VERSION 5.8 ;
BUSBITCHARS "[]" ;
DIVIDERCHAR "/" ;
UNITS
    DATABASE MICRONS 1000 ;
END UNITS

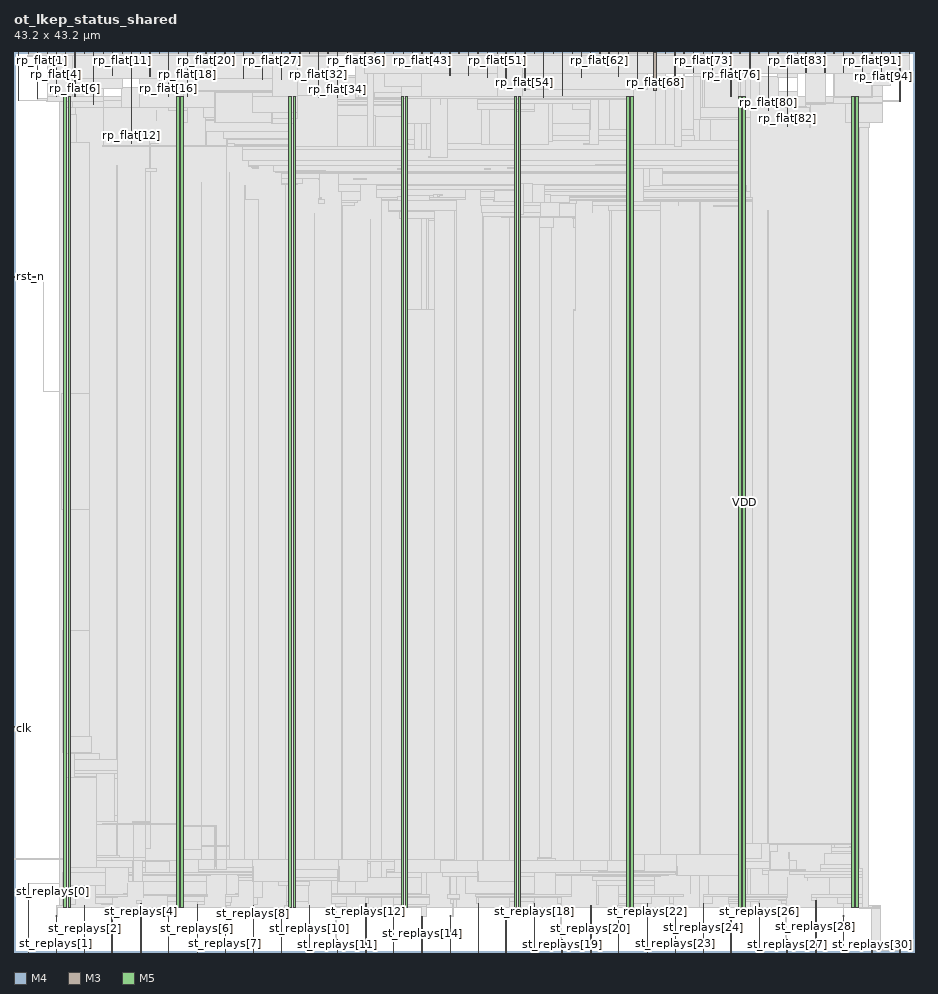
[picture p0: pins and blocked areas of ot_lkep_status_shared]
MACRO ot_lkep_status_shared
  FOREIGN ot_lkep_status_shared 0 0 ;
  CLASS BLOCK ;
  SIZE 43.2 BY 43.2 ;
  PIN clk
    DIRECTION INPUT ;
    USE SIGNAL ;
    PORT
      LAYER M4 ;
        RECT  0 10.8 0.084 10.824 ;
    END
    PORT
      LAYER M4 ;
        RECT  0.06 10.608 0.179 10.824 ;
    END
  END clk
  PIN rp_flat[0]
    DIRECTION INPUT ;
    USE SIGNAL ;
    PORT
      LAYER M3 ;
        RECT  0.216 43.162 0.234 43.2 ;
    END
    PORT
      LAYER M3 ;
        RECT  0.216 40.873 0.234 43.181 ;
    END
  END rp_flat[0]
  PIN rp_flat[10]
    DIRECTION INPUT ;
    USE SIGNAL ;
    PORT
      LAYER M3 ;
        RECT  4.716 43.162 4.734 43.2 ;
    END
    PORT
      LAYER M3 ;
        RECT  4.716 42.061 4.734 43.181 ;
    END
  END rp_flat[10]
  PIN rp_flat[11]
    DIRECTION INPUT ;
    USE SIGNAL ;
    PORT
      LAYER M5 ;
        RECT  5.184 43.116 5.208 43.2 ;
    END
  END rp_flat[11]
  PIN rp_flat[12]
    DIRECTION INPUT ;
    USE SIGNAL ;
    PORT
      LAYER M3 ;
        RECT  5.616 43.162 5.634 43.2 ;
    END
    PORT
      LAYER M3 ;
        RECT  5.616 38.785 5.634 43.181 ;
    END
  END rp_flat[12]
  PIN rp_flat[13]
    DIRECTION INPUT ;
    USE SIGNAL ;
    PORT
      LAYER M5 ;
        RECT  6.048 43.116 6.072 43.2 ;
    END
  END rp_flat[13]
  PIN rp_flat[14]
    DIRECTION INPUT ;
    USE SIGNAL ;
    PORT
      LAYER M3 ;
        RECT  6.516 43.162 6.534 43.2 ;
    END
    PORT
      LAYER M3 ;
        RECT  6.516 42.025 6.534 43.181 ;
    END
  END rp_flat[14]
  PIN rp_flat[15]
    DIRECTION INPUT ;
    USE SIGNAL ;
    PORT
      LAYER M5 ;
        RECT  6.96 43.116 6.984 43.2 ;
    END
  END rp_flat[15]
  PIN rp_flat[16]
    DIRECTION INPUT ;
    USE SIGNAL ;
    PORT
      LAYER M3 ;
        RECT  7.416 43.162 7.434 43.2 ;
    END
    PORT
      LAYER M3 ;
        RECT  7.416 41.057 7.434 43.181 ;
    END
  END rp_flat[16]
  PIN rp_flat[17]
    DIRECTION INPUT ;
    USE SIGNAL ;
    PORT
      LAYER M5 ;
        RECT  7.872 43.116 7.896 43.2 ;
    END
  END rp_flat[17]
  PIN rp_flat[18]
    DIRECTION INPUT ;
    USE SIGNAL ;
    PORT
      LAYER M3 ;
        RECT  8.316 43.162 8.334 43.2 ;
    END
    PORT
      LAYER M3 ;
        RECT  8.316 41.057 8.334 43.181 ;
    END
  END rp_flat[18]
  PIN rp_flat[19]
    DIRECTION INPUT ;
    USE SIGNAL ;
    PORT
      LAYER M5 ;
        RECT  8.784 43.116 8.808 43.2 ;
    END
  END rp_flat[19]
  PIN rp_flat[1]
    DIRECTION INPUT ;
    USE SIGNAL ;
    PORT
      LAYER M5 ;
        RECT  0.672 43.116 0.696 43.2 ;
    END
  END rp_flat[1]
  PIN rp_flat[20]
    DIRECTION INPUT ;
    USE SIGNAL ;
    PORT
      LAYER M3 ;
        RECT  9.216 43.162 9.234 43.2 ;
    END
    PORT
      LAYER M3 ;
        RECT  9.216 43.133 9.234 43.181 ;
    END
  END rp_flat[20]
  PIN rp_flat[21]
    DIRECTION INPUT ;
    USE SIGNAL ;
    PORT
      LAYER M5 ;
        RECT  9.648 43.116 9.672 43.2 ;
    END
  END rp_flat[21]
  PIN rp_flat[22]
    DIRECTION INPUT ;
    USE SIGNAL ;
    PORT
      LAYER M3 ;
        RECT  10.116 43.162 10.134 43.2 ;
    END
    PORT
      LAYER M3 ;
        RECT  10.116 43.133 10.134 43.181 ;
    END
  END rp_flat[22]
  PIN rp_flat[23]
    DIRECTION INPUT ;
    USE SIGNAL ;
    PORT
      LAYER M5 ;
        RECT  10.56 43.116 10.584 43.2 ;
    END
  END rp_flat[23]
  PIN rp_flat[24]
    DIRECTION INPUT ;
    USE SIGNAL ;
    PORT
      LAYER M3 ;
        RECT  11.016 43.162 11.034 43.2 ;
    END
    PORT
      LAYER M3 ;
        RECT  11.016 41.917 11.034 43.181 ;
    END
  END rp_flat[24]
  PIN rp_flat[25]
    DIRECTION INPUT ;
    USE SIGNAL ;
    PORT
      LAYER M5 ;
        RECT  11.472 43.116 11.496 43.2 ;
    END
  END rp_flat[25]
  PIN rp_flat[26]
    DIRECTION INPUT ;
    USE SIGNAL ;
    PORT
      LAYER M3 ;
        RECT  11.916 43.162 11.934 43.2 ;
    END
    PORT
      LAYER M3 ;
        RECT  11.916 41.885 11.934 43.181 ;
    END
  END rp_flat[26]
  PIN rp_flat[27]
    DIRECTION INPUT ;
    USE SIGNAL ;
    PORT
      LAYER M5 ;
        RECT  12.384 43.116 12.408 43.2 ;
    END
  END rp_flat[27]
  PIN rp_flat[28]
    DIRECTION INPUT ;
    USE SIGNAL ;
    PORT
      LAYER M3 ;
        RECT  12.816 43.162 12.834 43.2 ;
    END
    PORT
      LAYER M3 ;
        RECT  12.816 41.881 12.834 43.181 ;
    END
  END rp_flat[28]
  PIN rp_flat[29]
    DIRECTION INPUT ;
    USE SIGNAL ;
    PORT
      LAYER M5 ;
        RECT  13.248 43.116 13.272 43.2 ;
    END
  END rp_flat[29]
  PIN rp_flat[2]
    DIRECTION INPUT ;
    USE SIGNAL ;
    PORT
      LAYER M3 ;
        RECT  1.116 43.162 1.134 43.2 ;
    END
    PORT
      LAYER M3 ;
        RECT  1.116 40.945 1.134 43.181 ;
    END
  END rp_flat[2]
  PIN rp_flat[30]
    DIRECTION INPUT ;
    USE SIGNAL ;
    PORT
      LAYER M3 ;
        RECT  13.716 43.162 13.734 43.2 ;
    END
    PORT
      LAYER M3 ;
        RECT  13.716 43.141 13.734 43.181 ;
    END
  END rp_flat[30]
  PIN rp_flat[31]
    DIRECTION INPUT ;
    USE SIGNAL ;
    PORT
      LAYER M5 ;
        RECT  14.16 43.116 14.184 43.2 ;
    END
  END rp_flat[31]
  PIN rp_flat[32]
    DIRECTION INPUT ;
    USE SIGNAL ;
    PORT
      LAYER M3 ;
        RECT  14.616 43.162 14.634 43.2 ;
    END
    PORT
      LAYER M3 ;
        RECT  14.616 41.021 14.634 43.181 ;
    END
  END rp_flat[32]
  PIN rp_flat[33]
    DIRECTION INPUT ;
    USE SIGNAL ;
    PORT
      LAYER M5 ;
        RECT  15.072 43.116 15.096 43.2 ;
    END
  END rp_flat[33]
  PIN rp_flat[34]
    DIRECTION INPUT ;
    USE SIGNAL ;
    PORT
      LAYER M3 ;
        RECT  15.516 43.162 15.534 43.2 ;
    END
    PORT
      LAYER M3 ;
        RECT  15.516 41.009 15.534 43.181 ;
    END
  END rp_flat[34]
  PIN rp_flat[35]
    DIRECTION INPUT ;
    USE SIGNAL ;
    PORT
      LAYER M5 ;
        RECT  15.984 43.116 16.008 43.2 ;
    END
  END rp_flat[35]
  PIN rp_flat[36]
    DIRECTION INPUT ;
    USE SIGNAL ;
    PORT
      LAYER M3 ;
        RECT  16.416 43.162 16.434 43.2 ;
    END
    PORT
      LAYER M3 ;
        RECT  16.416 43.169 16.434 43.181 ;
    END
  END rp_flat[36]
  PIN rp_flat[37]
    DIRECTION INPUT ;
    USE SIGNAL ;
    PORT
      LAYER M5 ;
        RECT  16.848 43.116 16.872 43.2 ;
    END
  END rp_flat[37]
  PIN rp_flat[38]
    DIRECTION INPUT ;
    USE SIGNAL ;
    PORT
      LAYER M3 ;
        RECT  17.316 43.162 17.334 43.2 ;
    END
    PORT
      LAYER M3 ;
        RECT  17.316 43.169 17.334 43.181 ;
    END
  END rp_flat[38]
  PIN rp_flat[39]
    DIRECTION INPUT ;
    USE SIGNAL ;
    PORT
      LAYER M5 ;
        RECT  17.76 43.116 17.784 43.2 ;
    END
  END rp_flat[39]
  PIN rp_flat[3]
    DIRECTION INPUT ;
    USE SIGNAL ;
    PORT
      LAYER M5 ;
        RECT  1.584 43.116 1.608 43.2 ;
    END
  END rp_flat[3]
  PIN rp_flat[40]
    DIRECTION INPUT ;
    USE SIGNAL ;
    PORT
      LAYER M3 ;
        RECT  18.216 43.162 18.234 43.2 ;
    END
    PORT
      LAYER M3 ;
        RECT  18.216 43.133 18.234 43.181 ;
    END
  END rp_flat[40]
  PIN rp_flat[41]
    DIRECTION INPUT ;
    USE SIGNAL ;
    PORT
      LAYER M5 ;
        RECT  18.672 43.116 18.696 43.2 ;
    END
  END rp_flat[41]
  PIN rp_flat[42]
    DIRECTION INPUT ;
    USE SIGNAL ;
    PORT
      LAYER M3 ;
        RECT  19.116 43.162 19.134 43.2 ;
    END
    PORT
      LAYER M3 ;
        RECT  19.116 43.133 19.134 43.181 ;
    END
  END rp_flat[42]
  PIN rp_flat[43]
    DIRECTION INPUT ;
    USE SIGNAL ;
    PORT
      LAYER M5 ;
        RECT  19.584 43.116 19.608 43.2 ;
    END
  END rp_flat[43]
  PIN rp_flat[44]
    DIRECTION INPUT ;
    USE SIGNAL ;
    PORT
      LAYER M3 ;
        RECT  20.016 43.162 20.034 43.2 ;
    END
    PORT
      LAYER M3 ;
        RECT  20.016 43.141 20.106 43.169 ;
    END
    PORT
      LAYER M3 ;
        RECT  20.016 43.169 20.034 43.181 ;
    END
  END rp_flat[44]
  PIN rp_flat[45]
    DIRECTION INPUT ;
    USE SIGNAL ;
    PORT
      LAYER M5 ;
        RECT  20.448 43.116 20.472 43.2 ;
    END
  END rp_flat[45]
  PIN rp_flat[46]
    DIRECTION INPUT ;
    USE SIGNAL ;
    PORT
      LAYER M3 ;
        RECT  20.916 43.162 20.934 43.2 ;
    END
    PORT
      LAYER M3 ;
        RECT  20.916 42.053 20.934 43.181 ;
    END
  END rp_flat[46]
  PIN rp_flat[47]
    DIRECTION INPUT ;
    USE SIGNAL ;
    PORT
      LAYER M5 ;
        RECT  21.36 43.116 21.384 43.2 ;
    END
  END rp_flat[47]
  PIN rp_flat[48]
    DIRECTION INPUT ;
    USE SIGNAL ;
    PORT
      LAYER M3 ;
        RECT  21.816 43.162 21.834 43.2 ;
    END
    PORT
      LAYER M3 ;
        RECT  21.816 42.053 21.834 43.181 ;
    END
  END rp_flat[48]
  PIN rp_flat[49]
    DIRECTION INPUT ;
    USE SIGNAL ;
    PORT
      LAYER M5 ;
        RECT  22.272 43.116 22.296 43.2 ;
    END
  END rp_flat[49]
  PIN rp_flat[4]
    DIRECTION INPUT ;
    USE SIGNAL ;
    PORT
      LAYER M3 ;
        RECT  2.016 43.162 2.034 43.2 ;
    END
    PORT
      LAYER M3 ;
        RECT  2.016 41.057 2.034 43.181 ;
    END
  END rp_flat[4]
  PIN rp_flat[50]
    DIRECTION INPUT ;
    USE SIGNAL ;
    PORT
      LAYER M3 ;
        RECT  22.716 43.162 22.734 43.2 ;
    END
    PORT
      LAYER M3 ;
        RECT  22.716 41.981 22.734 43.181 ;
    END
  END rp_flat[50]
  PIN rp_flat[51]
    DIRECTION INPUT ;
    USE SIGNAL ;
    PORT
      LAYER M5 ;
        RECT  23.184 43.116 23.208 43.2 ;
    END
  END rp_flat[51]
  PIN rp_flat[52]
    DIRECTION INPUT ;
    USE SIGNAL ;
    PORT
      LAYER M3 ;
        RECT  23.616 43.162 23.634 43.2 ;
    END
    PORT
      LAYER M3 ;
        RECT  23.616 41.933 23.634 43.181 ;
    END
  END rp_flat[52]
  PIN rp_flat[53]
    DIRECTION INPUT ;
    USE SIGNAL ;
    PORT
      LAYER M5 ;
        RECT  24.048 43.116 24.072 43.2 ;
    END
  END rp_flat[53]
  PIN rp_flat[54]
    DIRECTION INPUT ;
    USE SIGNAL ;
    PORT
      LAYER M3 ;
        RECT  24.516 43.162 24.534 43.2 ;
    END
    PORT
      LAYER M3 ;
        RECT  24.516 41.357 24.534 43.181 ;
    END
  END rp_flat[54]
  PIN rp_flat[55]
    DIRECTION INPUT ;
    USE SIGNAL ;
    PORT
      LAYER M5 ;
        RECT  24.96 43.116 24.984 43.2 ;
    END
  END rp_flat[55]
  PIN rp_flat[56]
    DIRECTION INPUT ;
    USE SIGNAL ;
    PORT
      LAYER M3 ;
        RECT  25.416 43.162 25.434 43.2 ;
    END
    PORT
      LAYER M3 ;
        RECT  25.416 41.021 25.434 43.181 ;
    END
  END rp_flat[56]
  PIN rp_flat[57]
    DIRECTION INPUT ;
    USE SIGNAL ;
    PORT
      LAYER M5 ;
        RECT  25.872 43.116 25.896 43.2 ;
    END
  END rp_flat[57]
  PIN rp_flat[58]
    DIRECTION INPUT ;
    USE SIGNAL ;
    PORT
      LAYER M3 ;
        RECT  26.316 43.162 26.334 43.2 ;
    END
    PORT
      LAYER M3 ;
        RECT  26.316 41.099 26.334 43.181 ;
    END
  END rp_flat[58]
  PIN rp_flat[59]
    DIRECTION INPUT ;
    USE SIGNAL ;
    PORT
      LAYER M5 ;
        RECT  26.784 43.116 26.808 43.2 ;
    END
  END rp_flat[59]
  PIN rp_flat[5]
    DIRECTION INPUT ;
    USE SIGNAL ;
    PORT
      LAYER M5 ;
        RECT  2.448 43.116 2.472 43.2 ;
    END
  END rp_flat[5]
  PIN rp_flat[60]
    DIRECTION INPUT ;
    USE SIGNAL ;
    PORT
      LAYER M3 ;
        RECT  27.216 43.162 27.234 43.2 ;
    END
    PORT
      LAYER M3 ;
        RECT  27.216 41.981 27.234 43.181 ;
    END
  END rp_flat[60]
  PIN rp_flat[61]
    DIRECTION INPUT ;
    USE SIGNAL ;
    PORT
      LAYER M5 ;
        RECT  27.648 43.116 27.672 43.2 ;
    END
  END rp_flat[61]
  PIN rp_flat[62]
    DIRECTION INPUT ;
    USE SIGNAL ;
    PORT
      LAYER M3 ;
        RECT  28.116 43.162 28.134 43.2 ;
    END
    PORT
      LAYER M3 ;
        RECT  28.116 43.141 28.134 43.181 ;
    END
  END rp_flat[62]
  PIN rp_flat[63]
    DIRECTION INPUT ;
    USE SIGNAL ;
    PORT
      LAYER M5 ;
        RECT  28.56 43.116 28.584 43.2 ;
    END
  END rp_flat[63]
  PIN rp_flat[64]
    DIRECTION INPUT ;
    USE SIGNAL ;
    PORT
      LAYER M3 ;
        RECT  29.016 43.162 29.034 43.2 ;
    END
    PORT
      LAYER M3 ;
        RECT  29.016 42.029 29.034 43.181 ;
    END
  END rp_flat[64]
  PIN rp_flat[65]
    DIRECTION INPUT ;
    USE SIGNAL ;
    PORT
      LAYER M5 ;
        RECT  29.472 43.116 29.496 43.2 ;
    END
  END rp_flat[65]
  PIN rp_flat[66]
    DIRECTION INPUT ;
    USE SIGNAL ;
    PORT
      LAYER M3 ;
        RECT  29.916 43.162 29.934 43.2 ;
    END
    PORT
      LAYER M3 ;
        RECT  29.916 41.945 29.934 43.181 ;
    END
  END rp_flat[66]
  PIN rp_flat[67]
    DIRECTION INPUT ;
    USE SIGNAL ;
    PORT
      LAYER M5 ;
        RECT  30.384 43.116 30.408 43.2 ;
    END
  END rp_flat[67]
  PIN rp_flat[68]
    DIRECTION INPUT ;
    USE SIGNAL ;
    PORT
      LAYER M3 ;
        RECT  30.816 43.162 30.834 43.2 ;
    END
    PORT
      LAYER M3 ;
        RECT  30.708 41.369 30.834 43.169 ;
    END
    PORT
      LAYER M3 ;
        RECT  30.816 43.169 30.834 43.181 ;
    END
  END rp_flat[68]
  PIN rp_flat[69]
    DIRECTION INPUT ;
    USE SIGNAL ;
    PORT
      LAYER M5 ;
        RECT  31.248 43.116 31.272 43.2 ;
    END
  END rp_flat[69]
  PIN rp_flat[6]
    DIRECTION INPUT ;
    USE SIGNAL ;
    PORT
      LAYER M3 ;
        RECT  2.916 43.162 2.934 43.2 ;
    END
    PORT
      LAYER M3 ;
        RECT  2.916 41.057 2.934 43.181 ;
    END
  END rp_flat[6]
  PIN rp_flat[70]
    DIRECTION INPUT ;
    USE SIGNAL ;
    PORT
      LAYER M3 ;
        RECT  31.716 43.162 31.734 43.2 ;
    END
    PORT
      LAYER M3 ;
        RECT  31.716 41.909 31.734 43.181 ;
    END
  END rp_flat[70]
  PIN rp_flat[71]
    DIRECTION INPUT ;
    USE SIGNAL ;
    PORT
      LAYER M5 ;
        RECT  32.16 43.116 32.184 43.2 ;
    END
  END rp_flat[71]
  PIN rp_flat[72]
    DIRECTION INPUT ;
    USE SIGNAL ;
    PORT
      LAYER M3 ;
        RECT  32.616 43.162 32.634 43.2 ;
    END
    PORT
      LAYER M3 ;
        RECT  32.616 42.221 32.634 43.181 ;
    END
  END rp_flat[72]
  PIN rp_flat[73]
    DIRECTION INPUT ;
    USE SIGNAL ;
    PORT
      LAYER M5 ;
        RECT  33.072 43.116 33.096 43.2 ;
    END
  END rp_flat[73]
  PIN rp_flat[74]
    DIRECTION INPUT ;
    USE SIGNAL ;
    PORT
      LAYER M3 ;
        RECT  33.516 43.162 33.534 43.2 ;
    END
    PORT
      LAYER M3 ;
        RECT  33.516 42.221 33.534 43.181 ;
    END
  END rp_flat[74]
  PIN rp_flat[75]
    DIRECTION INPUT ;
    USE SIGNAL ;
    PORT
      LAYER M5 ;
        RECT  33.984 43.116 34.008 43.2 ;
    END
  END rp_flat[75]
  PIN rp_flat[76]
    DIRECTION INPUT ;
    USE SIGNAL ;
    PORT
      LAYER M3 ;
        RECT  34.416 43.162 34.434 43.2 ;
    END
    PORT
      LAYER M3 ;
        RECT  34.416 41.057 34.434 43.181 ;
    END
  END rp_flat[76]
  PIN rp_flat[77]
    DIRECTION INPUT ;
    USE SIGNAL ;
    PORT
      LAYER M5 ;
        RECT  34.848 43.116 34.872 43.2 ;
    END
  END rp_flat[77]
  PIN rp_flat[78]
    DIRECTION INPUT ;
    USE SIGNAL ;
    PORT
      LAYER M3 ;
        RECT  35.316 43.162 35.334 43.2 ;
    END
    PORT
      LAYER M3 ;
        RECT  35.316 42.221 35.334 43.181 ;
    END
  END rp_flat[78]
  PIN rp_flat[79]
    DIRECTION INPUT ;
    USE SIGNAL ;
    PORT
      LAYER M5 ;
        RECT  35.76 43.116 35.784 43.2 ;
    END
  END rp_flat[79]
  PIN rp_flat[7]
    DIRECTION INPUT ;
    USE SIGNAL ;
    PORT
      LAYER M5 ;
        RECT  3.36 43.116 3.384 43.2 ;
    END
  END rp_flat[7]
  PIN rp_flat[80]
    DIRECTION INPUT ;
    USE SIGNAL ;
    PORT
      LAYER M3 ;
        RECT  36.216 43.162 36.234 43.2 ;
    END
    PORT
      LAYER M3 ;
        RECT  36.216 40.369 36.234 43.181 ;
    END
  END rp_flat[80]
  PIN rp_flat[81]
    DIRECTION INPUT ;
    USE SIGNAL ;
    PORT
      LAYER M5 ;
        RECT  36.672 43.116 36.696 43.2 ;
    END
  END rp_flat[81]
  PIN rp_flat[82]
    DIRECTION INPUT ;
    USE SIGNAL ;
    PORT
      LAYER M3 ;
        RECT  37.116 43.162 37.134 43.2 ;
    END
    PORT
      LAYER M3 ;
        RECT  37.116 39.631 37.134 43.181 ;
    END
  END rp_flat[82]
  PIN rp_flat[83]
    DIRECTION INPUT ;
    USE SIGNAL ;
    PORT
      LAYER M5 ;
        RECT  37.584 43.116 37.608 43.2 ;
    END
  END rp_flat[83]
  PIN rp_flat[84]
    DIRECTION INPUT ;
    USE SIGNAL ;
    PORT
      LAYER M3 ;
        RECT  38.016 43.162 38.034 43.2 ;
    END
    PORT
      LAYER M3 ;
        RECT  38.016 42.221 38.034 43.181 ;
    END
  END rp_flat[84]
  PIN rp_flat[85]
    DIRECTION INPUT ;
    USE SIGNAL ;
    PORT
      LAYER M5 ;
        RECT  38.448 43.116 38.472 43.2 ;
    END
  END rp_flat[85]
  PIN rp_flat[86]
    DIRECTION INPUT ;
    USE SIGNAL ;
    PORT
      LAYER M3 ;
        RECT  38.916 43.162 38.934 43.2 ;
    END
    PORT
      LAYER M3 ;
        RECT  38.916 42.221 38.934 43.181 ;
    END
  END rp_flat[86]
  PIN rp_flat[87]
    DIRECTION INPUT ;
    USE SIGNAL ;
    PORT
      LAYER M5 ;
        RECT  39.36 43.116 39.384 43.2 ;
    END
  END rp_flat[87]
  PIN rp_flat[88]
    DIRECTION INPUT ;
    USE SIGNAL ;
    PORT
      LAYER M3 ;
        RECT  39.816 43.162 39.834 43.2 ;
    END
    PORT
      LAYER M3 ;
        RECT  39.816 42.221 39.834 43.181 ;
    END
  END rp_flat[88]
  PIN rp_flat[89]
    DIRECTION INPUT ;
    USE SIGNAL ;
    PORT
      LAYER M5 ;
        RECT  40.272 43.116 40.296 43.2 ;
    END
  END rp_flat[89]
  PIN rp_flat[8]
    DIRECTION INPUT ;
    USE SIGNAL ;
    PORT
      LAYER M3 ;
        RECT  3.816 43.162 3.834 43.2 ;
    END
    PORT
      LAYER M3 ;
        RECT  3.816 40.675 3.834 43.181 ;
    END
  END rp_flat[8]
  PIN rp_flat[90]
    DIRECTION INPUT ;
    USE SIGNAL ;
    PORT
      LAYER M3 ;
        RECT  40.716 43.162 40.734 43.2 ;
    END
    PORT
      LAYER M3 ;
        RECT  40.716 42.221 40.734 43.181 ;
    END
  END rp_flat[90]
  PIN rp_flat[91]
    DIRECTION INPUT ;
    USE SIGNAL ;
    PORT
      LAYER M5 ;
        RECT  41.184 43.116 41.208 43.2 ;
    END
  END rp_flat[91]
  PIN rp_flat[92]
    DIRECTION INPUT ;
    USE SIGNAL ;
    PORT
      LAYER M3 ;
        RECT  41.616 43.162 41.634 43.2 ;
    END
    PORT
      LAYER M3 ;
        RECT  41.616 42.221 41.634 43.181 ;
    END
  END rp_flat[92]
  PIN rp_flat[93]
    DIRECTION INPUT ;
    USE SIGNAL ;
    PORT
      LAYER M5 ;
        RECT  42.048 43.116 42.072 43.2 ;
    END
  END rp_flat[93]
  PIN rp_flat[94]
    DIRECTION INPUT ;
    USE SIGNAL ;
    PORT
      LAYER M3 ;
        RECT  42.516 43.162 42.534 43.2 ;
    END
    PORT
      LAYER M3 ;
        RECT  42.516 40.837 42.534 43.181 ;
    END
  END rp_flat[94]
  PIN rp_flat[95]
    DIRECTION INPUT ;
    USE SIGNAL ;
    PORT
      LAYER M5 ;
        RECT  42.96 43.116 42.984 43.2 ;
    END
  END rp_flat[95]
  PIN rp_flat[9]
    DIRECTION INPUT ;
    USE SIGNAL ;
    PORT
      LAYER M5 ;
        RECT  4.272 43.116 4.296 43.2 ;
    END
  END rp_flat[9]
  PIN rst_n
    DIRECTION INPUT ;
    USE SIGNAL ;
    PORT
      LAYER M4 ;
        RECT  0 32.4 0.084 32.424 ;
    END
    PORT
      LAYER M4 ;
        RECT  0.06 32.4 1.433 32.424 ;
    END
  END rst_n
  PIN st_replays[0]
    DIRECTION OUTPUT ;
    USE SIGNAL ;
    PORT
      LAYER M3 ;
        RECT  0.684 0 0.702 0.038 ;
    END
    PORT
      LAYER M3 ;
        RECT  0.684 0.012 0.702 3.299 ;
    END
  END st_replays[0]
  PIN st_replays[10]
    DIRECTION OUTPUT ;
    USE SIGNAL ;
    PORT
      LAYER M3 ;
        RECT  14.184 0 14.202 0.038 ;
    END
    PORT
      LAYER M3 ;
        RECT  14.184 0.012 14.202 2.219 ;
    END
  END st_replays[10]
  PIN st_replays[11]
    DIRECTION OUTPUT ;
    USE SIGNAL ;
    PORT
      LAYER M5 ;
        RECT  15.504 0 15.528 0.084 ;
    END
    PORT
      LAYER M5 ;
        RECT  15.504 0.016 15.528 0.611 ;
    END
  END st_replays[11]
  PIN st_replays[12]
    DIRECTION OUTPUT ;
    USE SIGNAL ;
    PORT
      LAYER M3 ;
        RECT  16.884 0 16.902 0.038 ;
    END
    PORT
      LAYER M3 ;
        RECT  16.884 0.012 16.902 2.335 ;
    END
  END st_replays[12]
  PIN st_replays[13]
    DIRECTION OUTPUT ;
    USE SIGNAL ;
    PORT
      LAYER M5 ;
        RECT  18.192 0 18.216 0.084 ;
    END
    PORT
      LAYER M5 ;
        RECT  18.192 0.016 18.216 1.763 ;
    END
  END st_replays[13]
  PIN st_replays[14]
    DIRECTION OUTPUT ;
    USE SIGNAL ;
    PORT
      LAYER M3 ;
        RECT  19.584 0 19.602 0.038 ;
    END
    PORT
      LAYER M3 ;
        RECT  19.584 0.012 19.602 1.723 ;
    END
  END st_replays[14]
  PIN st_replays[15]
    DIRECTION OUTPUT ;
    USE SIGNAL ;
    PORT
      LAYER M5 ;
        RECT  20.928 0 20.952 0.084 ;
    END
    PORT
      LAYER M5 ;
        RECT  20.928 0.016 20.952 1.763 ;
    END
  END st_replays[15]
  PIN st_replays[16]
    DIRECTION OUTPUT ;
    USE SIGNAL ;
    PORT
      LAYER M3 ;
        RECT  22.284 0 22.302 0.038 ;
    END
    PORT
      LAYER M3 ;
        RECT  22.284 0.012 22.302 2.335 ;
    END
  END st_replays[16]
  PIN st_replays[17]
    DIRECTION OUTPUT ;
    USE SIGNAL ;
    PORT
      LAYER M5 ;
        RECT  23.616 0 23.64 0.084 ;
    END
    PORT
      LAYER M5 ;
        RECT  23.616 0.016 23.64 1.763 ;
    END
  END st_replays[17]
  PIN st_replays[18]
    DIRECTION OUTPUT ;
    USE SIGNAL ;
    PORT
      LAYER M3 ;
        RECT  24.984 0 25.002 0.038 ;
    END
    PORT
      LAYER M3 ;
        RECT  24.984 0.012 25.002 2.335 ;
    END
  END st_replays[18]
  PIN st_replays[19]
    DIRECTION OUTPUT ;
    USE SIGNAL ;
    PORT
      LAYER M5 ;
        RECT  26.304 0 26.328 0.084 ;
    END
    PORT
      LAYER M5 ;
        RECT  26.304 0.016 26.328 0.611 ;
    END
  END st_replays[19]
  PIN st_replays[1]
    DIRECTION OUTPUT ;
    USE SIGNAL ;
    PORT
      LAYER M5 ;
        RECT  2.016 0 2.04 0.084 ;
    END
    PORT
      LAYER M5 ;
        RECT  2.016 0.016 2.04 1.763 ;
    END
  END st_replays[1]
  PIN st_replays[20]
    DIRECTION OUTPUT ;
    USE SIGNAL ;
    PORT
      LAYER M3 ;
        RECT  27.684 0 27.702 0.038 ;
    END
    PORT
      LAYER M3 ;
        RECT  27.684 0.012 27.702 2.219 ;
    END
  END st_replays[20]
  PIN st_replays[21]
    DIRECTION OUTPUT ;
    USE SIGNAL ;
    PORT
      LAYER M5 ;
        RECT  28.992 0 29.016 0.084 ;
    END
    PORT
      LAYER M5 ;
        RECT  28.992 0.016 29.016 1.763 ;
    END
  END st_replays[21]
  PIN st_replays[22]
    DIRECTION OUTPUT ;
    USE SIGNAL ;
    PORT
      LAYER M3 ;
        RECT  30.384 0 30.402 0.038 ;
    END
    PORT
      LAYER M3 ;
        RECT  30.384 0.012 30.402 2.335 ;
    END
  END st_replays[22]
  PIN st_replays[23]
    DIRECTION OUTPUT ;
    USE SIGNAL ;
    PORT
      LAYER M5 ;
        RECT  31.728 0 31.752 0.084 ;
    END
    PORT
      LAYER M5 ;
        RECT  31.728 0.016 31.752 1.763 ;
    END
  END st_replays[23]
  PIN st_replays[24]
    DIRECTION OUTPUT ;
    USE SIGNAL ;
    PORT
      LAYER M3 ;
        RECT  33.084 0 33.102 0.038 ;
    END
    PORT
      LAYER M3 ;
        RECT  33.084 0.012 33.102 2.335 ;
    END
  END st_replays[24]
  PIN st_replays[25]
    DIRECTION OUTPUT ;
    USE SIGNAL ;
    PORT
      LAYER M5 ;
        RECT  34.416 0 34.44 0.084 ;
    END
    PORT
      LAYER M5 ;
        RECT  34.416 0.016 34.44 1.763 ;
    END
  END st_replays[25]
  PIN st_replays[26]
    DIRECTION OUTPUT ;
    USE SIGNAL ;
    PORT
      LAYER M3 ;
        RECT  35.784 0 35.802 0.038 ;
    END
    PORT
      LAYER M3 ;
        RECT  35.784 0.012 35.802 2.335 ;
    END
  END st_replays[26]
  PIN st_replays[27]
    DIRECTION OUTPUT ;
    USE SIGNAL ;
    PORT
      LAYER M5 ;
        RECT  37.104 0 37.128 0.084 ;
    END
    PORT
      LAYER M5 ;
        RECT  37.104 0.016 37.128 0.611 ;
    END
  END st_replays[27]
  PIN st_replays[28]
    DIRECTION OUTPUT ;
    USE SIGNAL ;
    PORT
      LAYER M3 ;
        RECT  38.484 0 38.502 0.038 ;
    END
    PORT
      LAYER M3 ;
        RECT  38.484 0.012 38.502 2.461 ;
    END
  END st_replays[28]
  PIN st_replays[29]
    DIRECTION OUTPUT ;
    USE SIGNAL ;
    PORT
      LAYER M5 ;
        RECT  39.792 0 39.816 0.084 ;
    END
    PORT
      LAYER M5 ;
        RECT  39.792 0.016 39.816 1.763 ;
    END
  END st_replays[29]
  PIN st_replays[2]
    DIRECTION OUTPUT ;
    USE SIGNAL ;
    PORT
      LAYER M3 ;
        RECT  3.384 0 3.402 0.038 ;
    END
    PORT
      LAYER M3 ;
        RECT  3.384 0.012 3.402 2.219 ;
    END
  END st_replays[2]
  PIN st_replays[30]
    DIRECTION OUTPUT ;
    USE SIGNAL ;
    PORT
      LAYER M3 ;
        RECT  41.184 0 41.202 0.038 ;
    END
    PORT
      LAYER M3 ;
        RECT  41.184 0.012 41.202 0.091 ;
    END
  END st_replays[30]
  PIN st_replays[31]
    DIRECTION OUTPUT ;
    USE SIGNAL ;
    PORT
      LAYER M5 ;
        RECT  42.528 0 42.552 0.084 ;
    END
    PORT
      LAYER M5 ;
        RECT  42.528 0.016 42.552 0.131 ;
    END
  END st_replays[31]
  PIN st_replays[3]
    DIRECTION OUTPUT ;
    USE SIGNAL ;
    PORT
      LAYER M5 ;
        RECT  4.704 0 4.728 0.084 ;
    END
    PORT
      LAYER M5 ;
        RECT  4.704 0.016 4.728 1.763 ;
    END
  END st_replays[3]
  PIN st_replays[4]
    DIRECTION OUTPUT ;
    USE SIGNAL ;
    PORT
      LAYER M3 ;
        RECT  6.084 0 6.102 0.038 ;
    END
    PORT
      LAYER M3 ;
        RECT  6.084 0.012 6.102 2.335 ;
    END
  END st_replays[4]
  PIN st_replays[5]
    DIRECTION OUTPUT ;
    USE SIGNAL ;
    PORT
      LAYER M5 ;
        RECT  7.392 0 7.416 0.084 ;
    END
    PORT
      LAYER M5 ;
        RECT  7.392 0.016 7.416 1.763 ;
    END
  END st_replays[5]
  PIN st_replays[6]
    DIRECTION OUTPUT ;
    USE SIGNAL ;
    PORT
      LAYER M3 ;
        RECT  8.784 0 8.802 0.038 ;
    END
    PORT
      LAYER M3 ;
        RECT  8.784 0.012 8.802 2.263 ;
    END
  END st_replays[6]
  PIN st_replays[7]
    DIRECTION OUTPUT ;
    USE SIGNAL ;
    PORT
      LAYER M5 ;
        RECT  10.128 0 10.152 0.084 ;
    END
    PORT
      LAYER M5 ;
        RECT  10.128 0.016 10.152 1.763 ;
    END
  END st_replays[7]
  PIN st_replays[8]
    DIRECTION OUTPUT ;
    USE SIGNAL ;
    PORT
      LAYER M3 ;
        RECT  11.484 0 11.502 0.038 ;
    END
    PORT
      LAYER M3 ;
        RECT  11.484 0.012 11.502 2.219 ;
    END
  END st_replays[8]
  PIN st_replays[9]
    DIRECTION OUTPUT ;
    USE SIGNAL ;
    PORT
      LAYER M5 ;
        RECT  12.816 0 12.84 0.084 ;
    END
    PORT
      LAYER M5 ;
        RECT  12.816 0.016 12.84 1.763 ;
    END
  END st_replays[9]
  PIN VDD
    DIRECTION INOUT ;
    USE POWER ;
    PORT
      LAYER M5 ;
        RECT  40.392 2.151 40.512 41.049 ;
        RECT  34.992 2.151 35.112 41.049 ;
        RECT  29.592 2.151 29.712 41.049 ;
        RECT  24.192 2.151 24.312 41.049 ;
        RECT  18.792 2.151 18.912 41.049 ;
        RECT  13.392 2.151 13.512 41.049 ;
        RECT  7.992 2.151 8.112 41.049 ;
        RECT  2.592 2.151 2.712 41.049 ;
    END
  END VDD
  PIN VSS
    DIRECTION INOUT ;
    USE GROUND ;
    PORT
      LAYER M5 ;
        RECT  40.2 2.137 40.32 41.063 ;
        RECT  34.8 2.137 34.92 41.063 ;
        RECT  29.4 2.137 29.52 41.063 ;
        RECT  24 2.137 24.12 41.063 ;
        RECT  18.6 2.137 18.72 41.063 ;
        RECT  13.2 2.137 13.32 41.063 ;
        RECT  7.8 2.137 7.92 41.063 ;
        RECT  2.4 2.137 2.52 41.063 ;
    END
  END VSS
  # OT_OBS_CLOSED layer=M5 d_um=1.536 added=12
  OBS
    LAYER RVTN ;
     RECT  2.16 2.16 41.04 2.295 ;
     RECT  2.16 2.565 41.04 2.835 ;
     RECT  2.16 3.105 41.04 3.375 ;
     RECT  2.16 3.645 41.04 3.915 ;
     RECT  2.16 4.185 41.04 4.455 ;
     RECT  2.16 4.725 41.04 4.995 ;
     RECT  2.16 5.265 41.04 5.535 ;
     RECT  2.16 5.805 41.04 6.075 ;
     RECT  2.16 6.345 41.04 6.615 ;
     RECT  2.16 6.885 41.04 7.155 ;
     RECT  2.16 7.425 41.04 7.695 ;
     RECT  2.16 7.965 41.04 8.235 ;
     RECT  2.16 8.505 41.04 8.775 ;
     RECT  2.16 9.045 41.04 9.315 ;
     RECT  2.16 9.585 41.04 9.855 ;
     RECT  2.16 10.125 41.04 10.395 ;
     RECT  2.16 10.665 41.04 10.935 ;
     RECT  2.16 11.205 41.04 11.475 ;
     RECT  2.16 11.745 41.04 12.015 ;
     RECT  2.16 12.285 41.04 12.555 ;
     RECT  2.16 12.825 41.04 13.095 ;
     RECT  2.16 13.365 41.04 13.635 ;
     RECT  2.16 13.905 41.04 14.175 ;
     RECT  2.16 14.445 41.04 14.715 ;
     RECT  2.16 14.985 41.04 15.255 ;
     RECT  2.16 15.525 41.04 15.795 ;
     RECT  2.16 16.065 41.04 16.335 ;
     RECT  2.16 16.605 41.04 16.875 ;
     RECT  2.16 17.145 41.04 17.415 ;
     RECT  2.16 17.685 41.04 17.955 ;
     RECT  2.16 18.225 41.04 18.495 ;
     RECT  2.16 18.765 41.04 19.035 ;
     RECT  2.16 19.305 41.04 19.575 ;
     RECT  2.16 19.845 41.04 20.115 ;
     RECT  2.16 20.385 41.04 20.655 ;
     RECT  2.16 20.925 41.04 21.195 ;
     RECT  2.16 21.465 41.04 21.735 ;
     RECT  2.16 22.005 41.04 22.275 ;
     RECT  2.16 22.545 41.04 22.815 ;
     RECT  2.16 23.085 41.04 23.355 ;
     RECT  2.16 23.625 41.04 23.895 ;
     RECT  2.16 24.165 41.04 24.435 ;
     RECT  2.16 24.705 41.04 24.975 ;
     RECT  2.16 25.245 41.04 25.515 ;
     RECT  2.16 25.785 41.04 26.055 ;
     RECT  2.16 26.325 41.04 26.595 ;
     RECT  2.16 26.865 41.04 27.135 ;
     RECT  2.16 27.405 41.04 27.675 ;
     RECT  2.16 27.945 41.04 28.215 ;
     RECT  2.16 28.485 41.04 28.755 ;
     RECT  2.16 29.025 41.04 29.295 ;
     RECT  2.16 29.565 41.04 29.835 ;
     RECT  2.16 30.105 41.04 30.375 ;
     RECT  2.16 30.645 41.04 30.915 ;
     RECT  2.16 31.185 41.04 31.455 ;
     RECT  2.16 31.725 41.04 31.995 ;
     RECT  2.16 32.265 41.04 32.535 ;
     RECT  2.16 32.805 41.04 33.075 ;
     RECT  2.16 33.345 41.04 33.615 ;
     RECT  2.16 33.885 41.04 34.155 ;
     RECT  2.16 34.425 41.04 34.695 ;
     RECT  2.16 34.965 41.04 35.235 ;
     RECT  2.16 35.505 41.04 35.775 ;
     RECT  2.16 36.045 41.04 36.315 ;
     RECT  2.16 36.585 41.04 36.855 ;
     RECT  2.16 37.125 41.04 37.395 ;
     RECT  2.16 37.665 41.04 37.935 ;
     RECT  2.16 38.205 41.04 38.475 ;
     RECT  2.16 38.745 41.04 39.015 ;
     RECT  2.16 39.285 41.04 39.555 ;
     RECT  2.16 39.825 41.04 40.095 ;
     RECT  2.16 40.365 41.04 40.635 ;
     RECT  2.16 40.905 41.04 41.04 ;
    LAYER RVTP ;
     RECT  2.16 2.295 41.04 2.565 ;
     RECT  2.16 2.835 41.04 3.105 ;
     RECT  2.16 3.375 41.04 3.645 ;
     RECT  2.16 3.915 41.04 4.185 ;
     RECT  2.16 4.455 41.04 4.725 ;
     RECT  2.16 4.995 41.04 5.265 ;
     RECT  2.16 5.535 41.04 5.805 ;
     RECT  2.16 6.075 41.04 6.345 ;
     RECT  2.16 6.615 41.04 6.885 ;
     RECT  2.16 7.155 41.04 7.425 ;
     RECT  2.16 7.695 41.04 7.965 ;
     RECT  2.16 8.235 41.04 8.505 ;
     RECT  2.16 8.775 41.04 9.045 ;
     RECT  2.16 9.315 41.04 9.585 ;
     RECT  2.16 9.855 41.04 10.125 ;
     RECT  2.16 10.395 41.04 10.665 ;
     RECT  2.16 10.935 41.04 11.205 ;
     RECT  2.16 11.475 41.04 11.745 ;
     RECT  2.16 12.015 41.04 12.285 ;
     RECT  2.16 12.555 41.04 12.825 ;
     RECT  2.16 13.095 41.04 13.365 ;
     RECT  2.16 13.635 41.04 13.905 ;
     RECT  2.16 14.175 41.04 14.445 ;
     RECT  2.16 14.715 41.04 14.985 ;
     RECT  2.16 15.255 41.04 15.525 ;
     RECT  2.16 15.795 41.04 16.065 ;
     RECT  2.16 16.335 41.04 16.605 ;
     RECT  2.16 16.875 41.04 17.145 ;
     RECT  2.16 17.415 41.04 17.685 ;
     RECT  2.16 17.955 41.04 18.225 ;
     RECT  2.16 18.495 41.04 18.765 ;
     RECT  2.16 19.035 41.04 19.305 ;
     RECT  2.16 19.575 41.04 19.845 ;
     RECT  2.16 20.115 41.04 20.385 ;
     RECT  2.16 20.655 41.04 20.925 ;
     RECT  2.16 21.195 41.04 21.465 ;
     RECT  2.16 21.735 41.04 22.005 ;
     RECT  2.16 22.275 41.04 22.545 ;
     RECT  2.16 22.815 41.04 23.085 ;
     RECT  2.16 23.355 41.04 23.625 ;
     RECT  2.16 23.895 41.04 24.165 ;
     RECT  2.16 24.435 41.04 24.705 ;
     RECT  2.16 24.975 41.04 25.245 ;
     RECT  2.16 25.515 41.04 25.785 ;
     RECT  2.16 26.055 41.04 26.325 ;
     RECT  2.16 26.595 41.04 26.865 ;
     RECT  2.16 27.135 41.04 27.405 ;
     RECT  2.16 27.675 41.04 27.945 ;
     RECT  2.16 28.215 41.04 28.485 ;
     RECT  2.16 28.755 41.04 29.025 ;
     RECT  2.16 29.295 41.04 29.565 ;
     RECT  2.16 29.835 41.04 30.105 ;
     RECT  2.16 30.375 41.04 30.645 ;
     RECT  2.16 30.915 41.04 31.185 ;
     RECT  2.16 31.455 41.04 31.725 ;
     RECT  2.16 31.995 41.04 32.265 ;
     RECT  2.16 32.535 41.04 32.805 ;
     RECT  2.16 33.075 41.04 33.345 ;
     RECT  2.16 33.615 41.04 33.885 ;
     RECT  2.16 34.155 41.04 34.425 ;
     RECT  2.16 34.695 41.04 34.965 ;
     RECT  2.16 35.235 41.04 35.505 ;
     RECT  2.16 35.775 41.04 36.045 ;
     RECT  2.16 36.315 41.04 36.585 ;
     RECT  2.16 36.855 41.04 37.125 ;
     RECT  2.16 37.395 41.04 37.665 ;
     RECT  2.16 37.935 41.04 38.205 ;
     RECT  2.16 38.475 41.04 38.745 ;
     RECT  2.16 39.015 41.04 39.285 ;
     RECT  2.16 39.555 41.04 39.825 ;
     RECT  2.16 40.095 41.04 40.365 ;
     RECT  2.16 40.635 41.04 40.905 ;
    LAYER M1 ;
     RECT  2.16 2.151 41.04 41.049 ;
    LAYER M2 ;
     RECT  0.211 40.878 1.111 40.896 ;
     RECT  2.047 2.196 2.16 2.214 ;
     RECT  0.679 3.276 2.16 3.294 ;
     RECT  1.399 26.91 2.16 26.928 ;
     RECT  1.111 40.878 2.16 40.968 ;
     RECT  4.711 42.066 6.511 42.084 ;
     RECT  6.511 42.03 10.111 42.084 ;
     RECT  2.16 2.151 10.219 41.049 ;
     RECT  10.111 41.958 10.219 42.084 ;
     RECT  13.711 43.146 17.123 43.164 ;
     RECT  10.219 2.151 17.663 42.084 ;
     RECT  17.663 2.151 19.579 42.048 ;
     RECT  19.579 1.728 19.823 42.048 ;
     RECT  20.011 43.146 20.111 43.164 ;
     RECT  19.823 2.151 21.227 42.048 ;
     RECT  28.111 43.146 30.731 43.164 ;
     RECT  21.227 2.151 32.891 42.012 ;
     RECT  32.891 2.151 35.339 41.436 ;
     RECT  35.339 2.151 40.603 41.049 ;
     RECT  40.603 2.106 41.04 41.049 ;
     RECT  41.04 39.564 41.063 39.852 ;
     RECT  41.04 40.842 41.099 41.004 ;
     RECT  41.04 2.106 41.207 2.214 ;
     RECT  41.207 2.196 41.603 2.214 ;
     RECT  41.099 40.842 41.639 40.896 ;
     RECT  41.063 39.834 41.675 39.852 ;
     RECT  41.639 40.842 42.539 40.86 ;
    LAYER M3 ;
     RECT  41.184 0.091 41.598 2.101 ;
     RECT  40.608 2.101 41.598 2.129 ;
     RECT  2.052 1.723 2.07 2.143 ;
     RECT  7.38 1.723 7.398 2.143 ;
     RECT  12.96 1.723 12.978 2.143 ;
     RECT  18.216 1.723 18.234 2.143 ;
     RECT  23.76 1.723 23.778 2.143 ;
     RECT  28.98 1.723 28.998 2.143 ;
     RECT  34.344 1.723 34.362 2.143 ;
     RECT  39.816 1.723 39.834 2.143 ;
     RECT  40.608 2.129 40.734 2.143 ;
     RECT  15.444 0.571 15.462 2.191 ;
     RECT  18.216 2.143 18.705 2.191 ;
     RECT  19.584 1.723 19.818 2.191 ;
     RECT  2.052 2.143 2.505 2.219 ;
     RECT  12.96 2.143 13.305 2.219 ;
     RECT  28.98 2.143 29.505 2.219 ;
     RECT  41.58 2.129 41.598 2.219 ;
     RECT  4.716 1.723 4.734 2.227 ;
     RECT  10.152 1.723 10.17 2.227 ;
     RECT  2.34 2.219 2.505 2.263 ;
     RECT  4.572 2.227 4.734 2.263 ;
     RECT  18.216 2.191 19.818 2.263 ;
     RECT  4.176 2.263 4.734 2.335 ;
     RECT  15.444 2.191 15.966 2.335 ;
     RECT  21.06 1.723 21.078 2.335 ;
     RECT  26.244 0.571 26.262 2.335 ;
     RECT  29.016 2.219 29.505 2.335 ;
     RECT  31.644 1.723 31.662 2.335 ;
     RECT  34.344 2.143 34.905 2.335 ;
     RECT  37.044 0.571 37.062 2.335 ;
     RECT  39.816 2.143 40.734 2.335 ;
     RECT  10.152 2.227 10.386 2.371 ;
     RECT  7.38 2.143 7.905 2.413 ;
     RECT  8.784 2.263 9.162 2.413 ;
     RECT  13.104 2.219 13.305 2.413 ;
     RECT  14.112 2.335 14.13 2.413 ;
     RECT  23.76 2.143 24.105 2.413 ;
     RECT  24.912 2.335 25.002 2.413 ;
     RECT  34.308 2.335 34.905 2.413 ;
     RECT  35.712 2.335 35.802 2.413 ;
     RECT  36.864 2.335 37.062 2.461 ;
     RECT  5.868 2.335 6.102 2.489 ;
     RECT  20.952 2.335 21.078 2.497 ;
     RECT  34.308 2.413 35.802 2.497 ;
     RECT  36.72 2.461 37.062 2.497 ;
     RECT  20.952 2.497 21.366 2.569 ;
     RECT  3.924 2.335 4.734 2.605 ;
     RECT  11.52 2.263 11.682 2.605 ;
     RECT  16.884 2.335 17.01 2.605 ;
     RECT  18.216 2.263 19.962 2.605 ;
     RECT  22.212 2.335 22.302 2.605 ;
     RECT  23.76 2.413 25.002 2.605 ;
     RECT  26.064 2.335 26.262 2.605 ;
     RECT  34.308 2.497 37.062 2.605 ;
     RECT  38.268 2.461 38.502 2.605 ;
     RECT  39.528 2.335 40.734 2.605 ;
     RECT  3.924 2.605 4.95 2.641 ;
     RECT  7.38 2.413 9.162 2.641 ;
     RECT  10.152 2.371 10.458 2.641 ;
     RECT  15.264 2.335 15.966 2.641 ;
     RECT  16.884 2.605 19.962 2.641 ;
     RECT  22.212 2.605 26.262 2.641 ;
     RECT  29.016 2.335 30.618 2.641 ;
     RECT  31.464 2.335 31.662 2.641 ;
     RECT  33.084 2.335 33.534 2.641 ;
     RECT  34.308 2.605 37.134 2.641 ;
     RECT  6.192 2.605 6.21 2.731 ;
     RECT  7.38 2.641 9.306 2.731 ;
     RECT  3.924 2.641 5.454 2.759 ;
     RECT  6.192 2.731 9.306 2.759 ;
     RECT  10.152 2.641 10.782 2.759 ;
     RECT  15.264 2.641 19.962 2.759 ;
     RECT  20.808 2.569 21.366 2.759 ;
     RECT  22.14 2.641 26.766 2.759 ;
     RECT  29.016 2.641 32.13 2.759 ;
     RECT  33.084 2.641 37.134 2.759 ;
     RECT  38.268 2.605 40.734 2.759 ;
     RECT  22.14 2.759 24.966 2.803 ;
     RECT  5.256 2.759 5.454 2.831 ;
     RECT  10.62 2.759 10.782 2.831 ;
     RECT  15.264 2.759 19.566 2.831 ;
     RECT  2.34 2.263 2.934 3.181 ;
     RECT  3.924 2.759 4.41 3.181 ;
     RECT  13.104 2.413 14.13 3.181 ;
     RECT  27.972 2.263 28.062 3.181 ;
     RECT  29.016 2.759 30.762 3.181 ;
     RECT  5.436 2.831 5.454 3.299 ;
     RECT  6.192 2.759 9.234 3.379 ;
     RECT  11.52 2.605 11.934 3.379 ;
     RECT  12.708 3.181 14.166 3.379 ;
     RECT  10.764 2.831 10.782 3.451 ;
     RECT  11.52 3.379 14.166 3.451 ;
     RECT  15.264 2.831 15.534 3.451 ;
     RECT  27.972 3.181 30.762 3.451 ;
     RECT  10.764 3.451 15.534 3.569 ;
     RECT  16.38 2.831 19.566 3.569 ;
     RECT  37.116 2.759 37.134 3.569 ;
     RECT  38.088 3.415 38.106 3.577 ;
     RECT  39.132 2.759 40.734 3.577 ;
     RECT  20.916 2.759 20.934 3.613 ;
     RECT  21.672 2.803 24.966 3.613 ;
     RECT  27.756 3.451 30.762 3.613 ;
     RECT  25.992 2.759 26.766 3.649 ;
     RECT  27.756 3.613 31.05 3.649 ;
     RECT  32.472 2.803 32.49 3.649 ;
     RECT  5.472 3.379 9.234 3.685 ;
     RECT  10.764 3.569 12.114 3.685 ;
     RECT  5.472 3.685 9.414 3.721 ;
     RECT  10.728 3.685 12.114 3.721 ;
     RECT  25.992 3.649 31.41 3.721 ;
     RECT  36.216 2.759 36.234 3.721 ;
     RECT  37.944 3.577 40.734 3.721 ;
     RECT  17.892 3.569 19.566 3.811 ;
     RECT  20.592 3.613 24.966 3.811 ;
     RECT  25.992 3.721 31.734 3.811 ;
     RECT  32.472 3.649 32.598 3.811 ;
     RECT  17.892 3.811 24.966 3.835 ;
     RECT  2.34 3.181 4.41 3.839 ;
     RECT  5.472 3.721 12.114 3.839 ;
     RECT  25.992 3.811 32.598 3.839 ;
     RECT  7.488 3.839 11.718 3.869 ;
     RECT  25.992 3.839 27.198 3.869 ;
     RECT  17.892 3.835 25.074 3.875 ;
     RECT  28.044 3.839 32.598 3.875 ;
     RECT  37.224 3.721 40.734 3.875 ;
     RECT  28.476 3.875 32.598 3.92 ;
     RECT  35.928 3.721 36.234 3.931 ;
     RECT  17.892 3.875 24.297 3.947 ;
     RECT  25.992 3.869 26.874 3.955 ;
     RECT  18.615 3.947 22.842 3.965 ;
     RECT  37.224 3.875 37.962 3.965 ;
     RECT  25.056 3.875 25.074 3.991 ;
     RECT  25.92 3.955 26.874 3.991 ;
     RECT  28.584 3.92 32.598 3.991 ;
     RECT  33.336 2.759 35.19 3.991 ;
     RECT  35.928 3.931 36.27 3.991 ;
     RECT  12.888 3.569 15.534 4.013 ;
     RECT  25.056 3.991 26.874 4.019 ;
     RECT  38.736 3.875 40.734 4.019 ;
     RECT  2.415 3.839 4.41 4.075 ;
     RECT  5.472 3.839 6.318 4.075 ;
     RECT  14.4 4.013 15.534 4.075 ;
     RECT  7.815 3.869 11.718 4.109 ;
     RECT  13.032 4.013 13.662 4.109 ;
     RECT  14.4 4.075 15.606 4.109 ;
     RECT  25.128 4.019 26.874 4.109 ;
     RECT  10.188 4.109 11.718 4.145 ;
     RECT  15.588 4.109 15.606 4.145 ;
     RECT  38.736 4.019 40.59 4.217 ;
     RECT  16.38 3.569 17.118 4.261 ;
     RECT  26.748 4.109 26.874 4.379 ;
     RECT  37.224 3.965 37.566 4.379 ;
     RECT  28.584 3.991 36.306 4.397 ;
     RECT  10.332 4.145 11.718 4.415 ;
     RECT  15.732 4.261 17.118 4.415 ;
     RECT  18.615 3.965 22.518 4.415 ;
     RECT  29.415 4.397 36.306 4.415 ;
     RECT  18.615 4.415 21.15 4.445 ;
     RECT  29.415 4.415 31.95 4.451 ;
     RECT  32.94 4.415 36.306 4.451 ;
     RECT  25.128 4.109 26.01 4.487 ;
     RECT  37.224 4.379 37.242 4.495 ;
     RECT  25.128 4.487 25.794 4.523 ;
     RECT  2.415 4.075 6.318 4.559 ;
     RECT  2.415 4.559 5.058 4.621 ;
     RECT  2.376 4.621 5.058 4.649 ;
     RECT  2.376 4.649 3.654 4.685 ;
     RECT  29.415 4.451 31.554 4.685 ;
     RECT  38.88 4.217 40.59 4.721 ;
     RECT  37.152 4.495 37.242 4.757 ;
     RECT  36.18 4.451 36.306 4.801 ;
     RECT  39.24 4.721 40.59 4.829 ;
     RECT  2.415 4.685 3.654 4.919 ;
     RECT  7.815 4.109 9.018 4.919 ;
     RECT  6.3 4.559 6.318 4.963 ;
     RECT  39.24 4.829 40.497 5.027 ;
     RECT  40.104 5.027 40.497 5.063 ;
     RECT  9 4.919 9.018 5.071 ;
     RECT  10.332 4.415 10.35 5.071 ;
     RECT  9 5.071 10.35 5.117 ;
     RECT  39.24 5.027 39.366 5.189 ;
     RECT  36.18 4.801 36.63 5.213 ;
     RECT  39.24 5.189 39.258 5.213 ;
     RECT  2.415 4.919 3.618 6.139 ;
     RECT  4.932 4.649 4.986 6.139 ;
     RECT  6.3 4.963 6.534 6.235 ;
     RECT  2.415 6.139 4.986 6.269 ;
     RECT  5.724 6.235 6.534 6.275 ;
     RECT  4.824 6.269 4.986 6.539 ;
     RECT  4.824 6.539 4.95 8.311 ;
     RECT  2.415 6.269 3.69 8.395 ;
     RECT  2.415 8.395 3.942 8.581 ;
     RECT  4.824 8.311 4.986 8.581 ;
     RECT  2.415 8.581 4.986 8.699 ;
     RECT  2.415 8.699 4.95 9.239 ;
     RECT  2.415 9.239 4.086 9.509 ;
     RECT  2.415 9.509 3.726 9.553 ;
     RECT  2.34 9.553 3.726 10.355 ;
     RECT  2.34 10.355 3.618 15.449 ;
     RECT  2.376 15.449 3.618 21.235 ;
     RECT  2.304 21.235 3.618 26.789 ;
     RECT  26.856 4.379 26.874 30.811 ;
     RECT  18.615 4.445 20.178 30.839 ;
     RECT  26.856 30.811 26.946 30.839 ;
     RECT  1.404 26.905 1.422 32.429 ;
     RECT  25.2 4.523 25.794 34.771 ;
     RECT  26.928 30.839 26.946 34.771 ;
     RECT  19.908 30.839 20.178 35.131 ;
     RECT  17.1 4.415 17.118 35.159 ;
     RECT  18.615 30.839 18.897 35.203 ;
     RECT  19.872 35.131 20.178 35.203 ;
     RECT  26.856 34.771 26.946 35.203 ;
     RECT  23.796 3.947 24.297 35.275 ;
     RECT  25.2 34.771 25.902 35.275 ;
     RECT  26.784 35.203 26.946 35.275 ;
     RECT  23.4 35.275 26.946 35.303 ;
     RECT  22.5 4.415 22.518 35.311 ;
     RECT  23.4 35.303 25.254 35.311 ;
     RECT  14.4 4.109 14.418 35.429 ;
     RECT  22.5 35.311 25.254 35.509 ;
     RECT  18.504 35.203 20.178 35.545 ;
     RECT  17.964 35.545 20.178 35.581 ;
     RECT  21.132 4.445 21.15 35.581 ;
     RECT  28.584 4.397 28.674 35.581 ;
     RECT  29.415 4.685 31.05 35.581 ;
     RECT  36.18 5.213 36.198 35.609 ;
     RECT  15.732 4.415 15.75 35.815 ;
     RECT  22.464 35.509 25.254 35.815 ;
     RECT  27.756 35.509 27.774 35.815 ;
     RECT  28.512 35.581 31.05 35.815 ;
     RECT  26.172 35.303 26.946 35.941 ;
     RECT  15.732 35.815 16.362 35.977 ;
     RECT  27.756 35.815 31.05 36.013 ;
     RECT  31.896 35.815 31.914 36.013 ;
     RECT  32.94 4.451 35.442 36.013 ;
     RECT  15.732 35.977 16.47 36.049 ;
     RECT  17.964 35.581 21.258 36.049 ;
     RECT  26.172 35.941 27.018 36.049 ;
     RECT  27.756 36.013 35.442 36.049 ;
     RECT  26.172 36.049 35.442 36.085 ;
     RECT  11.088 4.415 11.718 36.113 ;
     RECT  14.616 35.941 14.886 36.113 ;
     RECT  17.64 36.049 21.258 36.121 ;
     RECT  22.392 35.815 25.254 36.121 ;
     RECT  26.028 36.085 35.442 36.121 ;
     RECT  14.616 36.113 14.742 36.149 ;
     RECT  17.64 36.121 21.654 36.211 ;
     RECT  14.652 36.149 14.742 36.239 ;
     RECT  22.392 36.121 35.442 36.239 ;
     RECT  22.392 36.239 35.37 36.509 ;
     RECT  15.732 36.049 16.65 36.517 ;
     RECT  17.388 36.211 21.654 36.589 ;
     RECT  22.392 36.509 35.154 36.589 ;
     RECT  11.088 36.113 11.106 36.779 ;
     RECT  17.388 36.589 35.154 36.779 ;
     RECT  13.032 4.109 13.497 36.823 ;
     RECT  15.552 36.517 16.65 36.823 ;
     RECT  17.388 36.779 35.097 36.823 ;
     RECT  12.96 36.823 13.626 36.859 ;
     RECT  12.816 36.859 13.626 36.895 ;
     RECT  9 5.117 9.018 36.959 ;
     RECT  14.652 36.239 14.67 37.057 ;
     RECT  12.816 36.895 13.842 37.129 ;
     RECT  14.616 37.057 14.67 37.129 ;
     RECT  12.816 37.129 14.67 37.363 ;
     RECT  15.552 36.823 35.097 37.363 ;
     RECT  12.816 37.363 35.097 37.399 ;
     RECT  10.332 5.117 10.35 37.427 ;
     RECT  6.3 6.275 6.534 37.471 ;
     RECT  12.528 37.399 35.097 37.471 ;
     RECT  6.3 37.471 6.858 37.589 ;
     RECT  11.448 37.597 11.718 37.669 ;
     RECT  11.412 37.669 11.718 37.705 ;
     RECT  4.932 9.239 4.95 37.733 ;
     RECT  11.268 37.705 11.718 37.741 ;
     RECT  12.456 37.471 35.097 37.741 ;
     RECT  11.268 37.741 35.097 37.975 ;
     RECT  11.088 37.975 35.097 38.011 ;
     RECT  10.98 38.011 35.097 38.543 ;
     RECT  10.98 38.543 19.242 38.776 ;
     RECT  10.548 38.776 19.242 38.779 ;
     RECT  6.516 37.589 6.534 38.821 ;
     RECT  2.415 26.789 3.618 38.849 ;
     RECT  6.516 38.821 6.93 38.939 ;
     RECT  19.98 38.543 35.097 38.939 ;
     RECT  10.26 38.779 19.242 39.011 ;
     RECT  10.26 39.011 14.922 39.055 ;
     RECT  6.516 38.939 6.534 39.209 ;
     RECT  19.98 38.939 32.67 39.209 ;
     RECT  9.216 38.749 9.234 39.361 ;
     RECT  10.044 39.055 14.922 39.361 ;
     RECT  40.215 5.063 40.497 39.559 ;
     RECT  15.696 39.011 19.242 39.757 ;
     RECT  19.98 39.209 32.634 39.757 ;
     RECT  7.815 4.919 8.097 39.793 ;
     RECT  40.215 39.559 41.058 39.793 ;
     RECT  39.924 39.793 41.058 39.829 ;
     RECT  9.216 39.361 14.922 39.901 ;
     RECT  15.696 39.757 32.634 39.901 ;
     RECT  9.216 39.901 32.634 39.979 ;
     RECT  33.444 38.939 35.097 39.979 ;
     RECT  9.216 39.979 35.097 40.063 ;
     RECT  2.415 38.849 3.006 40.199 ;
     RECT  6.84 39.901 6.858 40.397 ;
     RECT  7.815 39.793 8.334 40.405 ;
     RECT  38.196 39.595 38.214 40.555 ;
     RECT  9.108 40.063 35.37 40.637 ;
     RECT  9.144 40.637 35.37 40.667 ;
     RECT  38.016 40.555 38.214 40.675 ;
     RECT  9.144 40.667 12.222 40.703 ;
     RECT  38.016 40.675 38.934 40.711 ;
     RECT  39.924 39.829 41.67 40.711 ;
     RECT  11.232 40.703 12.222 40.739 ;
     RECT  38.016 40.711 41.67 40.781 ;
     RECT  13.032 40.667 35.37 40.801 ;
     RECT  9.144 40.703 10.458 40.829 ;
     RECT  11.232 40.739 12.042 40.829 ;
     RECT  13.032 40.801 35.478 40.829 ;
     RECT  11.304 40.829 12.042 40.901 ;
     RECT  13.215 40.829 35.478 40.901 ;
     RECT  2.415 40.199 2.934 40.909 ;
     RECT  16.38 40.901 35.478 40.937 ;
     RECT  16.38 40.937 27.738 40.973 ;
     RECT  28.476 40.937 35.478 40.973 ;
     RECT  9.216 40.829 10.458 41.009 ;
     RECT  11.628 40.901 12.042 41.009 ;
     RECT  13.215 40.901 15.534 41.009 ;
     RECT  16.38 40.973 20.106 41.009 ;
     RECT  20.844 40.973 21.942 41.009 ;
     RECT  31.716 40.973 35.478 41.009 ;
     RECT  13.215 41.009 14.778 41.021 ;
     RECT  17.316 41.009 20.106 41.021 ;
     RECT  25.416 40.973 27.558 41.021 ;
     RECT  2.016 40.909 2.934 41.057 ;
     RECT  7.416 40.405 8.334 41.057 ;
     RECT  13.215 41.021 13.878 41.057 ;
     RECT  22.716 40.973 24.534 41.057 ;
     RECT  34.416 41.009 35.37 41.057 ;
     RECT  39.816 40.781 41.67 41.057 ;
     RECT  26.316 41.021 27.558 41.099 ;
     RECT  13.644 41.057 13.878 41.165 ;
     RECT  28.476 40.973 30.834 41.309 ;
     RECT  9.216 41.009 10.242 41.324 ;
     RECT  24.48 41.057 24.534 41.357 ;
     RECT  28.512 41.309 30.834 41.369 ;
     RECT  20.916 41.009 21.942 41.405 ;
     RECT  28.512 41.369 29.934 41.441 ;
     RECT  40.716 41.057 41.67 41.645 ;
     RECT  11.628 41.009 11.934 41.885 ;
     RECT  31.716 41.009 31.806 41.909 ;
     RECT  22.716 41.057 23.634 41.933 ;
     RECT  28.584 41.441 29.934 41.945 ;
     RECT  22.716 41.933 22.842 41.981 ;
     RECT  27.216 41.099 27.378 41.981 ;
     RECT  16.38 41.009 16.542 41.989 ;
     RECT  17.316 41.021 19.134 41.989 ;
     RECT  28.584 41.945 29.034 42.029 ;
     RECT  20.916 41.405 21.834 42.053 ;
     RECT  16.38 41.989 19.134 42.221 ;
     RECT  32.616 41.009 33.534 42.221 ;
     RECT  35.316 41.057 35.37 42.221 ;
     RECT  38.016 40.781 38.934 42.221 ;
     RECT  39.816 41.057 39.942 42.221 ;
     RECT  40.716 41.645 41.634 42.221 ;
     RECT  13.86 41.165 13.878 43.085 ;
     RECT  9.216 41.324 10.134 43.133 ;
     RECT  18.216 42.221 19.134 43.133 ;
     RECT  20.088 41.021 20.106 43.141 ;
     RECT  16.416 42.221 17.334 43.169 ;
    LAYER M4 ;
     RECT  0.037 10.608 0.06 10.632 ;
     RECT  0.661 43.008 0.757 43.032 ;
     RECT  0.757 43.008 0.803 43.128 ;
     RECT  1.997 1.728 2.081 1.752 ;
     RECT  0.037 4.464 2.365 4.488 ;
     RECT  2.365 4.464 2.408 4.68 ;
     RECT  1.573 40.848 2.408 40.872 ;
     RECT  0.803 43.104 2.437 43.128 ;
     RECT  2.408 2.148 2.512 41.052 ;
     RECT  2.512 2.418 2.704 40.872 ;
     RECT  2.437 43.056 2.819 43.128 ;
     RECT  2.704 4.08 2.873 4.68 ;
     RECT  2.704 9.504 2.917 9.528 ;
     RECT  2.704 8.4 3.971 8.424 ;
     RECT  4.661 1.728 4.745 1.752 ;
     RECT  2.704 40.56 5.173 40.872 ;
     RECT  2.873 4.08 5.701 4.392 ;
     RECT  4.237 6.144 5.701 6.168 ;
     RECT  5.701 6.144 5.788 6.264 ;
     RECT  5.173 40.56 6.037 41.496 ;
     RECT  5.701 3.408 6.149 4.392 ;
     RECT  7.369 1.728 7.453 1.752 ;
     RECT  6.149 4.368 7.477 4.392 ;
     RECT  7.477 3.84 7.808 4.392 ;
     RECT  5.788 6.144 7.808 6.168 ;
     RECT  4.261 38.688 7.808 38.712 ;
     RECT  6.037 40.56 7.808 41.976 ;
     RECT  7.808 2.148 7.912 41.976 ;
     RECT  7.912 2.418 8.104 41.976 ;
     RECT  8.104 3.84 8.849 4.44 ;
     RECT  2.819 43.104 9.533 43.128 ;
     RECT  8.104 40.56 9.637 41.976 ;
     RECT  8.849 3.984 9.644 4.44 ;
     RECT  8.104 6.048 9.644 6.072 ;
     RECT  9.644 3.984 9.731 6.072 ;
     RECT  10.097 1.728 10.181 1.752 ;
     RECT  9.731 3.984 10.217 4.44 ;
     RECT  8.104 38.688 10.249 38.712 ;
     RECT  10.249 38.688 10.577 38.808 ;
     RECT  10.217 4.08 11.461 4.44 ;
     RECT  9.637 39.84 12.373 41.976 ;
     RECT  12.805 1.728 12.989 1.752 ;
     RECT  11.461 3.408 13.208 4.44 ;
     RECT  10.577 38.688 13.208 38.712 ;
     RECT  12.373 39.792 13.208 41.976 ;
     RECT  13.208 2.148 13.312 41.976 ;
     RECT  13.312 2.418 13.504 41.976 ;
     RECT  13.237 43.056 14.053 43.08 ;
     RECT  14.053 43.008 14.195 43.128 ;
     RECT  13.504 37.488 14.933 37.512 ;
     RECT  15.433 0.576 15.539 0.6 ;
     RECT  13.504 38.688 15.545 41.976 ;
     RECT  13.504 3.984 15.589 4.44 ;
     RECT  15.545 41.28 16.369 41.976 ;
     RECT  14.195 43.056 16.369 43.128 ;
     RECT  16.297 37.104 16.913 37.128 ;
     RECT  15.589 3.408 16.949 4.44 ;
     RECT  15.545 38.688 16.981 40.152 ;
     RECT  16.369 41.28 16.981 43.128 ;
     RECT  16.981 38.688 17.237 43.128 ;
     RECT  17.237 38.688 17.345 40.152 ;
     RECT  18.161 1.728 18.245 1.752 ;
     RECT  16.949 4.368 18.277 4.44 ;
     RECT  18.313 36.096 18.421 36.12 ;
     RECT  18.277 3.84 18.608 4.44 ;
     RECT  18.421 36.096 18.608 36.264 ;
     RECT  18.385 37.584 18.608 37.608 ;
     RECT  17.345 38.688 18.608 40.104 ;
     RECT  17.237 41.28 18.608 43.128 ;
     RECT  18.608 2.148 18.707 43.128 ;
     RECT  18.707 2.148 18.712 41.928 ;
     RECT  18.707 43.104 18.821 43.128 ;
     RECT  18.712 2.418 18.904 41.928 ;
     RECT  18.904 38.784 18.929 38.808 ;
     RECT  18.904 36.096 19.937 36.312 ;
     RECT  19.897 38.16 19.969 38.184 ;
     RECT  18.904 39.792 19.969 41.928 ;
     RECT  19.937 36.24 20.149 36.312 ;
     RECT  20.149 36.24 20.333 36.36 ;
     RECT  20.333 36.288 20.405 36.36 ;
     RECT  18.904 3.84 20.474 4.44 ;
     RECT  20.405 36.336 20.549 36.36 ;
     RECT  19.969 38.16 20.801 41.928 ;
     RECT  20.917 1.728 21.089 1.752 ;
     RECT  20.474 3.84 22.261 4.392 ;
     RECT  20.801 38.832 22.417 41.928 ;
     RECT  22.417 38.784 22.813 41.928 ;
     RECT  22.597 37.584 22.889 37.608 ;
     RECT  22.993 36.048 23.065 36.072 ;
     RECT  23.605 1.728 23.789 1.752 ;
     RECT  23.065 36.048 24.001 36.552 ;
     RECT  22.261 3.408 24.008 4.392 ;
     RECT  24.001 36 24.008 36.552 ;
     RECT  23.677 37.632 24.008 37.656 ;
     RECT  22.813 38.784 24.008 41.976 ;
     RECT  24.008 2.148 24.112 41.976 ;
     RECT  24.112 2.418 24.304 41.976 ;
     RECT  24.037 43.056 24.419 43.08 ;
     RECT  24.304 35.424 24.473 36.888 ;
     RECT  24.473 36 24.905 36.888 ;
     RECT  24.905 36 25.481 36.84 ;
     RECT  24.304 38.784 25.661 41.976 ;
     RECT  25.481 36 25.769 36.36 ;
     RECT  25.661 38.928 25.841 41.976 ;
     RECT  26.233 0.576 26.339 0.6 ;
     RECT  25.769 36 26.669 36.312 ;
     RECT  24.304 3.84 27.209 4.392 ;
     RECT  27.313 38.784 27.637 38.808 ;
     RECT  25.841 39.792 27.637 41.976 ;
     RECT  27.637 38.784 28.073 41.976 ;
     RECT  27.209 3.936 28.465 4.392 ;
     RECT  28.073 39.504 28.573 41.976 ;
     RECT  28.969 1.728 29.053 1.752 ;
     RECT  28.465 3.888 29.408 4.392 ;
     RECT  26.669 36.288 29.408 36.312 ;
     RECT  27.925 37.776 29.408 37.8 ;
     RECT  28.573 39.504 29.408 42.024 ;
     RECT  29.408 2.148 29.512 42.024 ;
     RECT  29.512 2.418 29.704 42.024 ;
     RECT  29.704 36.048 30.233 37.608 ;
     RECT  30.233 36.768 30.521 37.608 ;
     RECT  29.704 38.784 30.769 42.024 ;
     RECT  30.521 36.816 31.133 37.608 ;
     RECT  30.769 38.784 31.283 42.216 ;
     RECT  31.283 38.784 31.705 42.024 ;
     RECT  31.633 1.728 31.763 1.752 ;
     RECT  29.704 3.888 31.813 4.68 ;
     RECT  31.133 36.816 31.817 36.84 ;
     RECT  31.705 38.688 32.033 42.024 ;
     RECT  32.033 39.504 32.609 42.024 ;
     RECT  32.609 39.984 32.969 42.024 ;
     RECT  32.969 40.56 33.061 42.024 ;
     RECT  33.061 40.56 33.148 42.216 ;
     RECT  34.333 1.728 34.451 1.752 ;
     RECT  31.813 3.696 34.808 4.68 ;
     RECT  33.577 35.808 34.808 35.832 ;
     RECT  33.148 40.56 34.808 42.024 ;
     RECT  34.808 2.148 34.912 42.024 ;
     RECT  34.912 2.418 35.104 42.024 ;
     RECT  35.104 40.56 35.341 42.024 ;
     RECT  35.341 40.56 35.795 42.216 ;
     RECT  35.104 4.368 36.241 5.208 ;
     RECT  36.241 3.936 36.281 5.208 ;
     RECT  35.795 40.56 36.707 42.024 ;
     RECT  37.033 0.576 37.139 0.6 ;
     RECT  36.707 40.56 37.619 41.304 ;
     RECT  36.281 3.936 37.973 3.96 ;
     RECT  37.619 40.56 38.045 40.584 ;
     RECT  38.185 42.192 38.483 42.216 ;
     RECT  39.761 1.728 39.845 1.752 ;
     RECT  36.281 5.184 40.208 5.208 ;
     RECT  39.308 40.752 40.208 40.776 ;
     RECT  40.208 2.148 40.312 41.052 ;
     RECT  40.312 2.418 40.504 41.052 ;
     RECT  40.504 41.04 41.029 41.052 ;
     RECT  41.029 41.04 41.219 41.064 ;
     RECT  39.913 42.192 41.641 42.216 ;
     RECT  41.641 41.616 42.083 42.216 ;
     RECT  41.569 0.096 42.563 0.12 ;
     RECT  42.083 42.192 42.995 42.216 ;
    LAYER M5 ;
     RECT  2.4 2.137 2.52 2.151 ;
     RECT  7.8 2.137 7.92 2.151 ;
     RECT  13.2 2.137 13.32 2.151 ;
     RECT  18.6 2.137 18.72 2.151 ;
     RECT  24 2.137 24.12 2.151 ;
     RECT  29.4 2.137 29.52 2.151 ;
     RECT  34.8 2.137 34.92 2.151 ;
     RECT  40.2 2.137 40.32 2.151 ;
     RECT  22.272 3.397 22.296 3.875 ;
     RECT  29.4 2.151 29.712 3.925 ;
     RECT  11.472 3.397 11.496 4.115 ;
     RECT  15.6 3.397 15.624 4.115 ;
     RECT  31.824 3.685 31.848 4.115 ;
     RECT  34.8 2.151 35.112 4.501 ;
     RECT  29.4 3.925 30.264 4.691 ;
     RECT  34.8 4.501 35.88 5.219 ;
     RECT  9.696 4.117 9.72 6.083 ;
     RECT  5.712 3.397 5.736 6.275 ;
     RECT  2.4 2.151 2.712 8.389 ;
     RECT  3.936 4.069 3.96 8.435 ;
     RECT  2.4 8.389 2.904 9.539 ;
     RECT  0.048 4.453 0.072 10.597 ;
     RECT  0.048 10.597 0.168 10.643 ;
     RECT  0.144 10.643 0.168 10.835 ;
     RECT  13.2 2.151 13.512 39.781 ;
     RECT  12.384 39.781 13.512 40.021 ;
     RECT  12.384 40.021 13.608 40.309 ;
     RECT  24 2.151 24.312 40.357 ;
     RECT  24 40.357 24.984 40.453 ;
     RECT  27.648 39.493 27.672 40.453 ;
     RECT  2.4 9.539 2.712 40.549 ;
     RECT  22.272 40.453 24.984 40.741 ;
     RECT  26.784 40.453 27.672 40.741 ;
     RECT  40.2 2.151 40.512 40.741 ;
     RECT  2.4 40.549 2.808 40.837 ;
     RECT  4.272 38.677 4.296 40.837 ;
     RECT  22.272 40.741 27.672 40.933 ;
     RECT  29.4 4.691 29.712 40.933 ;
     RECT  18.6 2.151 18.912 40.981 ;
     RECT  20.448 40.693 20.472 40.981 ;
     RECT  22.272 40.933 29.712 40.981 ;
     RECT  39.36 40.741 40.512 41.029 ;
     RECT  34.8 5.219 35.112 41.049 ;
     RECT  1.584 40.837 4.296 41.063 ;
     RECT  11.472 40.309 13.608 41.063 ;
     RECT  18.6 40.981 29.712 41.063 ;
     RECT  34.8 41.049 34.92 41.063 ;
     RECT  39.36 41.029 41.208 41.063 ;
     RECT  9.648 39.829 9.672 41.269 ;
     RECT  11.472 41.063 12.408 41.269 ;
     RECT  7.8 2.151 8.112 41.317 ;
     RECT  9.648 41.269 12.408 41.317 ;
     RECT  7.8 41.317 12.408 41.365 ;
     RECT  24.384 41.063 29.712 41.413 ;
     RECT  2.784 41.063 4.296 41.461 ;
     RECT  41.184 41.063 41.208 41.605 ;
     RECT  34.8 41.063 34.872 41.893 ;
     RECT  2.784 41.461 5.208 41.941 ;
     RECT  6.96 41.365 12.408 41.941 ;
     RECT  37.584 41.269 37.608 41.989 ;
     RECT  17.76 41.557 17.784 42.181 ;
     RECT  19.584 41.063 23.208 42.181 ;
     RECT  24.384 41.413 30.408 42.181 ;
     RECT  32.16 41.941 32.184 42.181 ;
     RECT  33.984 41.893 34.872 42.181 ;
     RECT  36.672 41.989 37.608 42.181 ;
     RECT  39.36 41.063 39.384 42.181 ;
     RECT  41.184 41.605 42.072 42.181 ;
     RECT  1.584 41.063 1.608 42.997 ;
     RECT  13.584 41.063 13.608 42.997 ;
     RECT  15.072 41.125 15.096 42.997 ;
     RECT  0.672 42.997 1.608 43.045 ;
     RECT  2.784 41.941 12.408 43.045 ;
     RECT  13.584 42.997 15.096 43.045 ;
     RECT  16.848 42.181 23.208 43.045 ;
     RECT  24.384 42.181 42.984 43.045 ;
     RECT  0.672 43.045 42.984 43.152 ;
     RECT  2.712 4.069 3.936 8.389 ;
     RECT  2.904 8.389 3.936 8.435 ;
     RECT  2.808 40.549 4.272 40.837 ;
     RECT  34.92 41.049 35.112 41.063 ;
     RECT  1.608 41.063 2.784 43.045 ;
     RECT  12.408 41.063 13.584 43.045 ;
     RECT  18.6 41.063 19.584 41.557 ;
     RECT  23.208 41.063 24.384 43.045 ;
     RECT  34.872 41.063 35.112 42.181 ;
     RECT  39.384 41.063 41.184 42.181 ;
     RECT  13.608 41.125 15.072 42.997 ;
     RECT  17.784 41.557 19.584 42.181 ;
  END
END ot_lkep_status_shared
END LIBRARY
